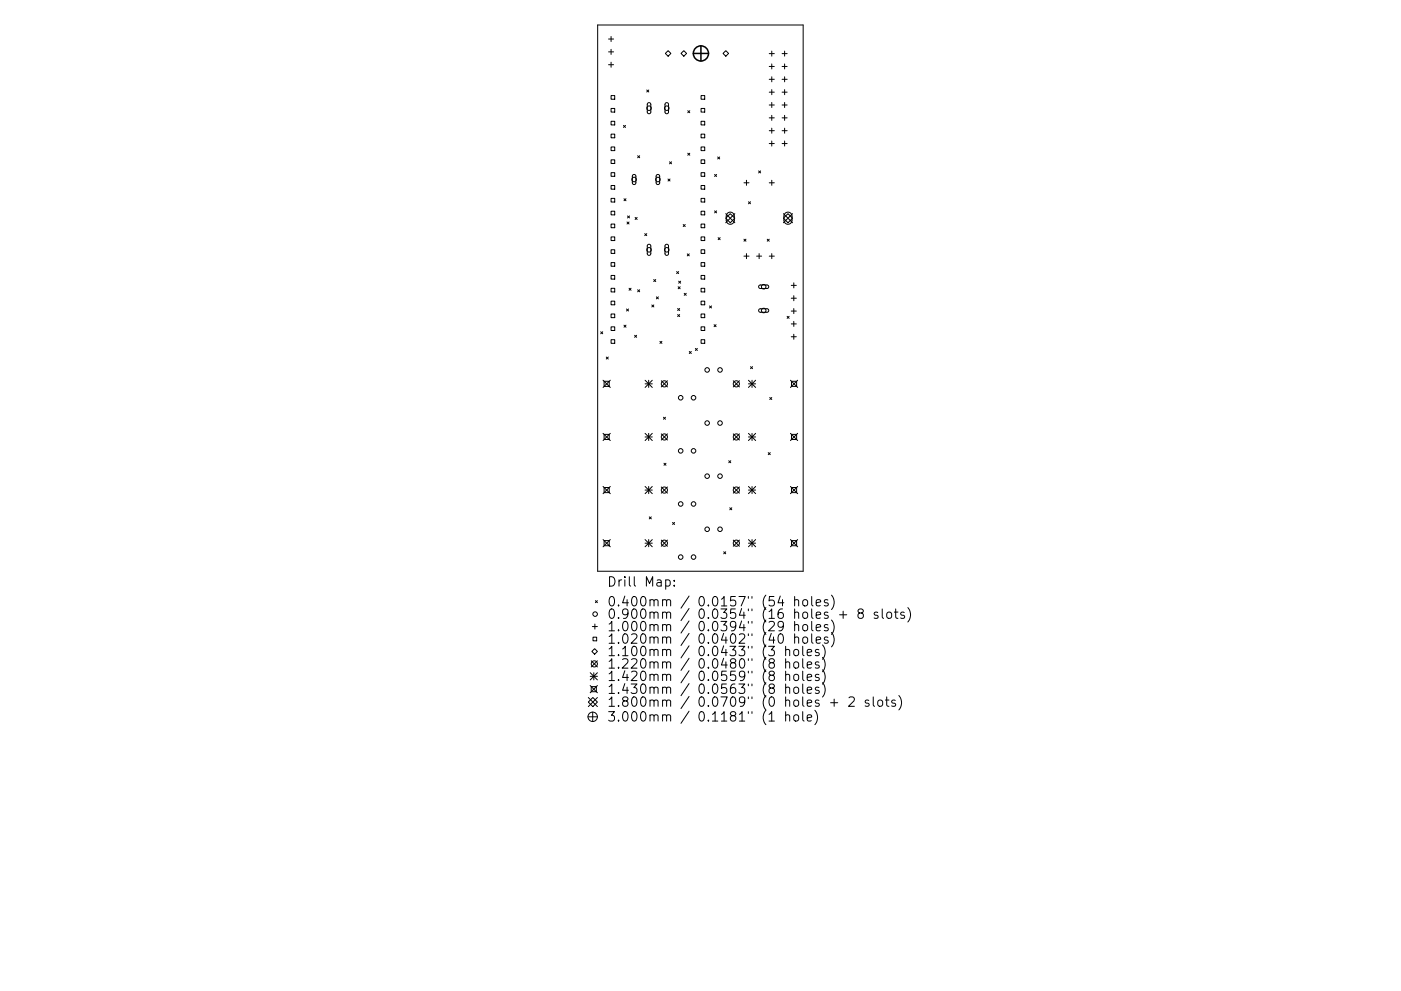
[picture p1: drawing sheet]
<svg xmlns="http://www.w3.org/2000/svg" width="297mm" height="210mm" viewBox="0 0 297 210" stroke-linecap="round" stroke-linejoin="round" font-family="sans-serif">
<defs><g id="words">
<g font-size="2.8">
<text x="128.7" y="124.5">Drill Map:</text>
<text x="128.7" y="128.7">0.400mm / 0.0157&quot; (54 holes)</text>
<text x="128.7" y="131.3">0.900mm / 0.0354&quot; (16 holes + 8 slots)</text>
<text x="128.7" y="133.9">1.000mm / 0.0394&quot; (29 holes)</text>
<text x="128.7" y="136.6">1.020mm / 0.0402&quot; (40 holes)</text>
<text x="128.7" y="139.2">1.100mm / 0.0433&quot; (3 holes)</text>
<text x="128.7" y="141.9">1.220mm / 0.0480&quot; (8 holes)</text>
<text x="128.7" y="144.5">1.420mm / 0.0559&quot; (8 holes)</text>
<text x="128.7" y="147.2">1.430mm / 0.0563&quot; (8 holes)</text>
<text x="128.7" y="150">1.800mm / 0.0709&quot; (0 holes + 2 slots)</text>
<text x="128.7" y="153.1">3.000mm / 0.1181&quot; (1 hole)</text>
</g>
</g></defs>
<g fill="none" stroke="#000" stroke-width=".21">
<path d="M126.7 5.3h43.6v115.9h-43.6zM129 8.3h1.1M129 11h1.1M129 13.7h1.1M129.6 7.7v1.1M129.6 10.5v1M129.6 13.2v1.1M137.1 19.1l.5 .4M137.6 19.1l-.5 .4M141.7 10.7l.5 .6-.5 .6-.6-.6zM145 10.7l.6 .6-.6 .6-.6-.6zM153.3 11.3l.6-.6 .6 .6-.6 .6z"/>
<path d="M163.1 11.4h1.1M163.1 14.1h1.1M163.1 16.8h1.1M163.1 19.6h1.1M163.6 10.8v1.1M163.6 13.6v1M163.6 16.3v1.1M163.6 19v1.1M165.8 11.4h1.1M165.8 14.1h1.1M165.8 16.8h1.1M165.8 19.6h1.1"/>
<path d="M166.4 10.8v1.1M166.4 13.6v1M166.4 16.3v1.1M166.4 19v1.1M129.6 20.3h.7v.8h-.7zM129.6 23h.7v.8h-.7zM129.6 25.7h.7v.8h-.7zM129.6 28.5h.7v.7h-.7zM129.6 31.2h.7v.8h-.7zM129.6 33.9h.7v.8h-.7zM129.6 36.6h.7v.8h-.7zM129.6 39.4h.7v.7h-.7z"/>
<path d="M132.2 26.6l.4 .4M132.6 26.6l-.4 .4M134.2 37.1l.3-.1 .3 .3v1.5l-.3 .4-.3-.1-.1-.3zM135.2 33l.4 .5M135.6 33l-.4 .5M137.3 21.9l.4-.1 .3 .3v1.7l-.3 .3h-.3l-.2-.3zM139.2 37.1l.4-.1 .3 .3v1.5l-.3 .4-.3-.1-.2-.3zM141.1 21.9l.4-.1 .2 .3v1.7l-.3 .3h-.3l-.1-.3zM141.6 38l.5 .4M142 34.3l.4 .5M142.1 38l-.5 .4M142.4 34.3l-.4 .5"/>
<path d="M145.8 23.5l.4 .4M145.8 32.5l.4 .4M146.2 23.5l-.4 .4M146.2 32.5l-.4 .4M148.6 20.3h.8v.8h-.8zM148.6 23h.8v.8h-.8zM148.6 25.7h.8v.8h-.8zM148.6 28.5h.8v.7h-.8zM148.6 31.2h.8v.8h-.8zM148.6 33.9h.8v.8h-.8zM148.6 36.6h.8v.8h-.8zM148.6 39.4h.8v.7h-.8z"/>
<path d="M151.5 37l.4 .4M151.9 37l-.4 .4M152.2 33.3l.4 .4M152.6 33.3l-.4 .4M157.7 38.8h1.1M158.3 38.2v1.1M160.8 36.3l.5 .4M161.3 36.3l-.5 .4M163.1 22.3h1.1M163.1 25h1.1M163.1 27.7h1.1M163.1 30.5h1.1"/>
<path d="M163.1 38.8h1.1M163.6 21.7v1.1M163.6 24.5v1M163.6 27.2v1.1M163.6 29.9v1.1M163.6 38.2v1.1M165.8 22.3h1.1M165.8 25h1.1M165.8 27.7h1.1M165.8 30.5h1.1M166.4 21.7v1.1M166.4 24.5v1"/>
<path d="M166.4 27.2v1.1M166.4 29.9v1.1M129.6 42.1h.7v.8h-.7zM129.6 44.8h.7v.8h-.7zM129.6 47.5h.7v.8h-.7zM129.6 50.3h.7v.7h-.7zM129.6 53h.7v.8h-.7zM129.6 55.7h.7v.8h-.7zM129.6 58.4h.7v.8h-.7zM132.3 42.2l.4 .4M132.7 42.2l-.4 .4M132.9 47.1l.5 .4"/>
<path d="M133 45.8l.5 .4M133.4 47.1l-.5 .4M133.5 45.8l-.5 .4M134.7 46.1l.4 .5M135.1 46.1l-.4 .5M136.7 49.6l.4 .4M137.1 49.6l-.4 .4M137.3 51.9l.4-.1 .3 .3v1.8l-.3 .3-.3-.1-.2-.2zM138.6 59.3l.4 .4M139 59.3l-.4 .4M141.1 51.9l.4-.1 .2 .3v1.8l-.3 .3-.3-.1-.1-.2zM143.5 57.6l.4 .4"/>
<path d="M143.9 57.6l-.4 .4M143.9 59.7l.4 .4M144.3 59.7l-.4 .4M144.9 47.6l.4 .5M145.3 47.6l-.4 .5M145.7 53.9l.4 .4M146.1 53.9l-.4 .4M148.6 42.1h.8v.8h-.8zM148.6 44.8h.8v.8h-.8zM148.6 47.5h.8v.8h-.8zM148.6 50.3h.8v.7h-.8zM148.6 53h.8v.8h-.8z"/>
<path d="M148.6 55.7h.8v.8h-.8zM148.6 58.4h.8v.8h-.8zM151.5 44.7l.4 .5M151.9 44.7l-.4 .5M152.3 50.4l.4 .5M152.7 50.4l-.4 .5M153.9 46.3l.9-1 1 1-1 1zM153.9 45.3l1.9 2M154.2 45.3a.86 .86 0 0 1 1-.2 .86 .86 0 0 1 .5 .8v.8a.86 .86 0 0 1-.9 .9 .86 .86 0 0 1-.8-.9v-1zM155.8 45.3l-1.9 2M157.7 50.7l.5 .5M157.7 54.3h1.1"/>
<path d="M158.2 50.7l-.5 .5M158.3 53.8v1.1M158.7 42.8l.4 .4M159.1 42.8l-.4 .4M160.4 54.3h1.1M160.9 53.8v1.1M162.7 50.7l.4 .5M163.1 50.7l-.4 .5M163.1 54.3h1.1M163.6 53.8v1.1M166.1 45.3l1.9 2M166.5 45.3a.86 .86 0 0 1 .9-.2 .86 .86 0 0 1 .5 .8v.8a.86 .86 0 0 1-.8 .9 .86 .86 0 0 1-.9-.9v-1z"/>
<path d="M167.1 45.3l.9 1-.9 1-1-1zM168 45.3l-1.9 2M127.4 70.4l.4 .4M127.8 70.4l-.4 .4M128.5 75.8l.5 .4M129 75.8l-.5 .4M129.6 61.2h.7v.7h-.7zM129.6 63.9h.7v.8h-.7zM129.6 66.6h.7v.8h-.7zM129.6 69.3h.7v.8h-.7zM129.6 72.1h.7v.7h-.7zM132.3 69l.4 .4"/>
<path d="M132.7 69l-.4 .4M132.8 65.6l.5 .4M133.3 65.6l-.5 .4M133.4 61.2l.4 .4M133.8 61.2l-.4 .4M134.6 71.1l.4 .5M135 71.1l-.4 .5M135.2 61.5l.4 .4M135.6 61.5l-.4 .4M138.2 64.7l.4 .4M138.6 64.7l-.4 .4M139.2 63l.4 .4"/>
<path d="M139.6 63l-.4 .4M139.9 72.4l.4 .5M140.3 72.4l-.4 .5M143.7 65.5l.4 .4M143.7 66.7l.4 .5M143.8 60.8l.4 .5M144.1 65.5l-.4 .4M144.1 66.7l-.4 .5M144.2 60.8l-.4 .5M145.1 62.2l.4 .5M145.5 62.2l-.4 .5M146.1 74.6l.5 .4"/>
<path d="M146.6 74.6l-.5 .4M147.4 73.9l.5 .5M147.9 73.9l-.5 .5M148.6 61.2h.8v.7h-.8zM148.6 63.9h.8v.8h-.8zM148.6 66.6h.8v.8h-.8zM148.6 69.3h.8v.8h-.8zM148.6 72.1h.8v.7h-.8zM150.4 64.9l.5 .4M150.9 64.9l-.5 .4M151.4 68.9l.4 .4M151.8 68.9l-.4 .4"/>
<path d="M159.1 77.8l.5 .4M159.6 77.8l-.5 .4M161 60.6l1.7-.1 .2 .1 .1 .3-.3 .3h-1.5l-.3-.2zM161 65.6l1.7-.1 .2 .2 .1 .2-.3 .3h-1.5l-.3-.2zM166.9 67.1l.4 .4M167.3 67.1l-.4 .4M167.8 60.5h1M167.8 63.3h1M167.8 66h1M167.8 68.7h1M167.8 71.4h1M168.3 60v1.1"/>
<path d="M168.3 62.7v1.1M168.3 65.5v1M168.3 68.2v1.1M168.3 70.9v1.1M127.9 80.7l1.5 1.5M127.9 91.9l1.5 1.6M128.1 80.9h1.1v1.1h-1.1zM128.1 92.2h1.1v1.1h-1.1zM129.4 80.7l-1.5 1.5M129.4 91.9l-1.5 1.6M136.8 80.7l1.5 1.5M136.8 81.4h1.5"/>
<path d="M136.8 91.9l1.5 1.6M136.8 92.7h1.5M137.5 80.7v1.5M137.5 91.9v1.6M138.3 80.7l-1.5 1.5M138.3 91.9l-1.5 1.6M140.2 80.8l1.3 1.3M140.2 92.1l1.3 1.3M140.7 88.5l.4 .5M140.8 98.3l.4 .4M141.1 88.5l-.4 .5M141.2 98.3l-.4 .4"/>
<path d="M141.5 80.8l-1.3 1.3M141.5 92.1l-1.3 1.3M154.5 97.8l.4 .4M154.9 97.8l-.4 .4M155.5 92.1l1.3 1.3M155.5 80.8l1.3 1.3M156.8 80.8l-1.3 1.3M156.8 92.1l-1.3 1.3M158.7 81.4h1.5M158.7 92.7h1.5M158.7 80.7l1.5 1.5M158.7 91.9l1.5 1.6"/>
<path d="M159.4 80.7v1.5M159.4 91.9v1.6M160.2 80.7l-1.5 1.5M160.2 91.9l-1.5 1.6M162.9 96l.4 .5M163.2 84.3l.4 .5M163.3 96l-.4 .5M163.6 84.3l-.4 .5M167.6 80.7l1.5 1.5M167.6 91.9l1.5 1.6M167.8 80.9h1.1v1.1h-1.1zM167.8 92.2h1.1v1.1h-1.1z"/>
<path d="M169.1 80.7l-1.5 1.5M169.1 91.9l-1.5 1.6M127.9 103.2l1.5 1.5M127.9 114.5l1.5 1.5M128.1 103.4h1.1v1.1h-1.1zM128.1 114.7h1.1v1.1h-1.1zM129.4 103.2l-1.5 1.5M129.4 114.5l-1.5 1.5M136.8 103.2l1.5 1.5M136.8 104h1.5M136.8 114.5l1.5 1.5M136.8 115.2h1.5"/>
<path d="M137.5 103.2v1.5M137.5 114.5v1.5M137.7 109.7l.4 .4M138.1 109.7l-.4 .4M138.3 103.2l-1.5 1.5M138.3 114.5l-1.5 1.5M140.2 103.3l1.3 1.3M140.2 114.6l1.3 1.3M141.5 103.3l-1.3 1.3M141.5 114.6l-1.3 1.3M142.6 110.8l.4 .5M143 110.8l-.4 .5"/>
<path d="M153.4 117.1l.5 .4M153.9 117.1l-.5 .4M154.7 107.7l.5 .5M155.2 107.7l-.5 .5M155.5 103.3l1.3 1.3M155.5 114.6l1.3 1.3M156.8 103.3l-1.3 1.3M156.8 114.6l-1.3 1.3M158.7 104h1.5M158.7 115.2h1.5M158.7 103.2l1.5 1.5M158.7 114.5l1.5 1.5"/>
<path d="M159.4 103.2v1.5M159.4 114.5v1.5M160.2 103.2l-1.5 1.5M160.2 114.5l-1.5 1.5M167.6 103.2l1.5 1.5M167.6 114.5l1.5 1.5M167.8 103.4h1.1v1.1h-1.1zM167.8 114.7h1.1v1.1h-1.1zM169.1 103.2l-1.5 1.5M169.1 114.5l-1.5 1.5M125.5 138.2l.6-.6 .6 .6-.6 .6zM125.6 132.9h1.1"/>
<path d="M125.7 135.2h.8v.8h-.8zM126.1 132.4v1.1M126.2 127.4l.5 .5M126.7 127.4l-.5 .5M141.1 123.1l.6-.1 .4 .4v.6l-.2 .3h-.8M143 124.2v.2M143 123.1v.2M165.1 134.7l.5-.2a1.25 1.25 0 0 1 0 2l-.4-.1-.2-.3v-.9zM165.4 126.5l-.4 1.4h1.2M166.1 132.7l-.4 .4-.6-.1-.1-.3v-.5l.1-.3 .6-.1 .3 .2a1.32 1.32 0 0 1-.5 1.8h-.4M166.6 138a.5 .5 0 0 1 .8 .1v1M166.6 137.1v2"/>
<path d="M166.6 139.8v2M168.4 138l.1-.1a.54 .54 0 0 1 .8 .3l-.1 .7a.54 .54 0 0 1-.5 .2 .54 .54 0 0 1-.4-.4zM168.5 127.4l.3-.2 .4 .1 .1 1.3M168.5 132.7l.3-.2 .4 .1 .1 1.2M168.5 135.3l.3-.2 .4 .1 .1 1.3M168.5 126.6v2M168.5 131.8v2M168.5 134.5v2M170.2 137.1v1.7l.3 .3M170.2 139.8v1.7l.3 .3M170.3 127.4l.3-.2a.54 .54 0 0 1 .6 .4v.6a.54 .54 0 0 1-.5 .4 .54 .54 0 0 1-.5-.4zM170.3 132.7a.54 .54 0 0 1 .5-.2 .54 .54 0 0 1 .4 .4v.6a.54 .54 0 0 1-.5 .4 .54 .54 0 0 1-.5-.4z"/>
<path d="M170.3 135.3a.54 .54 0 0 1 .5-.2 .54 .54 0 0 1 .4 .4v.6a.54 .54 0 0 1-.5 .4 .54 .54 0 0 1-.5-.4zM171.1 138.5l1-.2-.1-.4-.6-.1-.3 .3 .1 .9h.8M172.1 126.6v1.7l.3 .3M172.1 131.8v1.8l.3 .2M172.1 134.5v1.7l.3 .3M173 127.9l1-.2-.1-.4-.6-.1-.3 .3 .1 1h.8M173 133.2l1-.2-.1-.4-.6-.1-.3 .3 .1 .9h.8M173 135.8l1-.2-.1-.4-.6-.1-.3 .3 .1 1h.8M173.6 137.9l-.5-.1-.2 .3 .1 .3 .6 .1v.5h-.7M174.4 136.8a2.29 2.29 0 0 1 0 3.1M174.4 139.5a2.29 2.29 0 0 1 0 3M175.5 127.3l-.5-.1-.2 .3 .1 .3 .6 .2v.5h-.7"/>
<path d="M175.5 132.6l-.5-.1-.2 .3 .1 .3 .6 .2v.4h-.7M175.5 135.2l-.5-.1-.2 .3 .1 .3 .6 .2v.5h-.7M176.3 126.3a2.29 2.29 0 0 1 0 3M176.3 131.6a2.29 2.29 0 0 1 0 3M176.3 134.2a2.29 2.29 0 0 1 0 3M178 130.4h1.5M178.8 129.7v1.5M182.3 130.1l-.4-.4 .1-.3 .3-.2 .6 .1 .1 .3v.3l-.9 .2-.2 .3v.4l.4 .4 .6-.1 .1-.3v-.4l-.3-.3M186.1 130l-.5-.1-.3 .2 .1 .3 .7 .2v.5h-.8M187 129.2v1.7l.3 .3M188.1 130.1a.54 .54 0 0 1 .5-.2 .54 .54 0 0 1 .4 .3v.6a.54 .54 0 0 1-.5 .4 .54 .54 0 0 1-.5-.4zM189.6 129.9h.8"/>
<path d="M189.9 129.2v1.7l.1 .2 .4 .1M191.7 130l-.5-.1-.2 .2v.3l.7 .2v.5h-.7M192.5 128.9a2.29 2.29 0 0 1 0 3.1M124.7 152.1h2M124.7 148l2 1.9M125.1 145.4l1.6 1.6M125.1 142.7l1.6 1.6M125.1 143.5h1.6M125.4 145.7h1v1.1h-1zM125.4 140.2l1.3 1.3M125.7 151.1v2M125.7 148l1 1-1 .9-1-.9z"/>
<path d="M125.9 142.7v1.6M126.7 140.2l-1.3 1.3M126.7 142.7l-1.6 1.6M126.7 145.4l-1.6 1.6M126.7 148l-2 1.9M163 151.6l.6-.6v2M163 153h1.2M166.6 140.6a.5 .5 0 0 1 .8 .1v1.1M166.6 143.3a.5 .5 0 0 1 .8 0v1.1M166.6 146a.5 .5 0 0 1 .8 .1v1M166.6 151.8a.5 .5 0 0 1 .8 .1v1.1M166.6 142.4v2"/>
<path d="M166.6 145.1v2M166.6 151v2M168.4 140.6l.1-.1a.54 .54 0 0 1 .8 .3l-.1 .8a.54 .54 0 0 1-.5 .2 .54 .54 0 0 1-.4-.4zM168.4 143.3l.1-.1a.54 .54 0 0 1 .8 .2l-.1 .8a.54 .54 0 0 1-.5 .2 .54 .54 0 0 1-.4-.4zM168.4 146l.1-.1a.54 .54 0 0 1 .8 .3l-.1 .7a.54 .54 0 0 1-.5 .2 .54 .54 0 0 1-.4-.4zM168.4 151.8l.1-.1a.54 .54 0 0 1 .8 .3l-.1 .8a.54 .54 0 0 1-.5 .2 .54 .54 0 0 1-.4-.4zM170.2 142.4v1.7l.3 .3M170.2 145.1v1.7l.3 .3M170.2 151v1.7l.3 .3M171.1 141.1l1-.2-.1-.4-.6-.1-.3 .3 .1 1h.8M171.1 143.7l1-.2-.1-.3-.6-.1-.3 .2 .1 1h.8M171.1 146.5l1-.2-.1-.4-.6-.1-.3 .3 .1 .9h.8"/>
<path d="M171.1 152.3l1-.2-.1-.4h-.6l-.3 .2 .1 1h.8M172.8 150.7a2.29 2.29 0 0 1 0 3M173.6 140.5l-.5-.1-.2 .3 .1 .3 .6 .2v.5h-.7M173.6 143.2l-.5-.1-.2 .2 .1 .3 .6 .2v.5h-.7M173.6 145.9l-.5-.1-.2 .3 .1 .3 .6 .1v.5h-.7M174.4 142.1a2.29 2.29 0 0 1 0 3.1M174.4 144.8a2.29 2.29 0 0 1 0 3.1M176.1 149.1h1.5M176.9 148.3v1.6M180 148l.3-.1 .7 .1a.54 .54 0 0 1 0 .7l-1.1 1.2h1.2M184.2 148.6l-.5-.1-.3 .3 .1 .3 .7 .2v.5h-.8M185.1 147.9v1.7l.3 .3"/>
<path d="M186.2 148.7a.54 .54 0 0 1 .5-.2 .54 .54 0 0 1 .4 .4v.6a.54 .54 0 0 1-.5 .4 .54 .54 0 0 1-.5-.4zM187.7 148.5h.8M188 147.9v1.7l.1 .2 .4 .1M189.8 148.6l-.5-.1-.3 .3 .1 .3 .7 .2v.5h-.8M190.6 147.6a2.29 2.29 0 0 1 0 3"/>
<circle cx="134.4" cy="38.1" r=".48"/>
<circle cx="137.6" cy="23" r=".48"/>
<circle cx="139.5" cy="38.1" r=".48"/>
<circle cx="141.4" cy="23" r=".48"/>
<circle cx="137.6" cy="53" r=".48"/>
<circle cx="141.4" cy="53" r=".48"/>
<circle cx="149.9" cy="78.5" r=".48"/>
<circle cx="152.7" cy="78.5" r=".48"/>
<circle cx="161.9" cy="60.8" r=".48"/>
<circle cx="161.9" cy="65.9" r=".48"/>
<circle cx="140.9" cy="81.4" r=".65"/>
<circle cx="140.9" cy="92.7" r=".65"/>
<circle cx="144.3" cy="84.4" r=".48"/>
<circle cx="144.3" cy="95.7" r=".48"/>
<circle cx="147" cy="84.4" r=".48"/>
<circle cx="147" cy="95.7" r=".48"/>
<circle cx="149.9" cy="89.8" r=".48"/>
<circle cx="152.7" cy="89.8" r=".48"/>
<circle cx="156.1" cy="81.4" r=".65"/>
<circle cx="156.1" cy="92.7" r=".65"/>
<circle cx="140.9" cy="104" r=".65"/>
<circle cx="140.9" cy="115.2" r=".65"/>
<circle cx="144.3" cy="118.2" r=".48"/>
<circle cx="144.3" cy="106.9" r=".48"/>
<circle cx="147" cy="118.2" r=".48"/>
<circle cx="147" cy="106.9" r=".48"/>
<circle cx="149.9" cy="101" r=".48"/>
<circle cx="149.9" cy="112.3" r=".48"/>
<circle cx="152.7" cy="101" r=".48"/>
<circle cx="152.7" cy="112.3" r=".48"/>
<circle cx="156.1" cy="104" r=".65"/>
<circle cx="156.1" cy="115.2" r=".65"/>
<circle cx="126.2" cy="130.3" r=".48"/>
<circle cx="125.7" cy="152.1" r="1"/>
<circle cx="126" cy="140.9" r=".65"/>
</g>
<g fill="none" stroke="#000" stroke-width=".32">
<path d="M147 11.3h3.2M148.6 9.7v3.2"/>
<circle cx="148.6" cy="11.3" r="1.61"/>
</g>
<use href="#words"/>
</svg>
